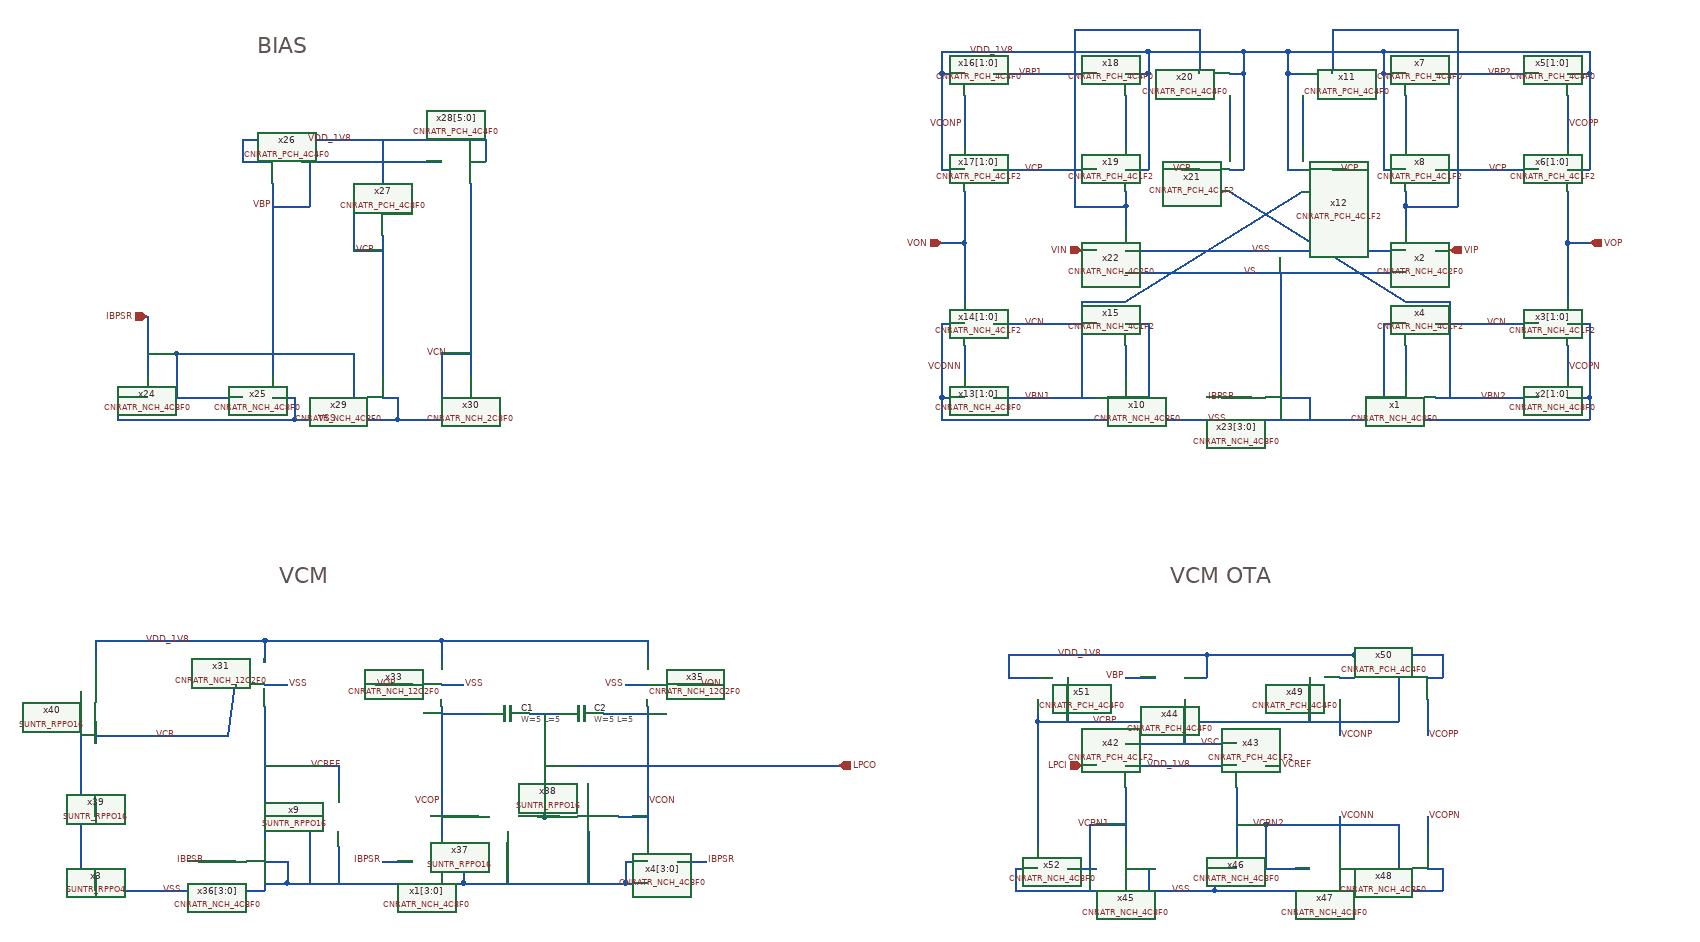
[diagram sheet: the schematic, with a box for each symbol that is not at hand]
v {xschem version=3.4.6 file_version=1.2}
G {}
K {}
V {}
S {}
E {}
T {BIAS} 530 -1300 0 0 1 1 {}
T {VCM} 560 -580 0 0 1 1 {}
T {VCM OTA} 1770 -580 0 0 1 1 {}
N 2060 -1250 2090 -1250 {
lab=VDD_1V8}
N 2060 -1280 2060 -1250 {
lab=VDD_1V8}
N 2060 -1280 2090 -1280 {
lab=VDD_1V8}
N 2310 -1250 2340 -1250 {
lab=VDD_1V8}
N 2340 -1280 2340 -1250 {
lab=VDD_1V8}
N 2310 -1280 2340 -1280 {
lab=VDD_1V8}
N 2310 -1220 2310 -1150 {
lab=VCOPP}
N 2090 -1220 2090 -1150 {
lab=#net1}
N 2060 -1120 2090 -1120 {
lab=VDD_1V8}
N 2060 -1250 2060 -1120 {
lab=VDD_1V8}
N 2310 -1120 2340 -1120 {
lab=VDD_1V8}
N 2340 -1250 2340 -1120 {
lab=VDD_1V8}
N 2090 -880 2090 -840 {
lab=#net2}
N 2060 -910 2090 -910 {
lab=VSS}
N 2060 -910 2060 -780 {
lab=VSS}
N 2060 -780 2090 -780 {
lab=VSS}
N 2060 -810 2090 -810 {
lab=VSS}
N 2310 -810 2340 -810 {
lab=VSS}
N 2340 -810 2340 -780 {
lab=VSS}
N 2310 -780 2340 -780 {
lab=VSS}
N 2310 -880 2310 -840 {
lab=VCOPN}
N 2310 -910 2340 -910 {
lab=VSS}
N 2340 -910 2340 -810 {
lab=VSS}
N 2090 -1280 2310 -1280 {
lab=VDD_1V8}
N 2130 -810 2270 -810 {
lab=VBN2}
N 2130 -1250 2270 -1250 {
lab=VBP2}
N 2090 -1090 2090 -1070 {
lab=VBP2}
N 2090 -940 2150 -940 {
lab=VBN2}
N 2150 -940 2150 -810 {
lab=VBN2}
N 2090 -780 2310 -780 {
lab=VSS}
N 1950 -1280 2060 -1280 {
lab=VDD_1V8}
N 1930 -1280 1950 -1280 {
lab=VDD_1V8}
N 1930 -1280 1930 -1250 {
lab=VDD_1V8}
N 1930 -1250 1950 -1250 {
lab=VDD_1V8}
N 1930 -1250 1930 -1120 {
lab=VDD_1V8}
N 1930 -1120 1950 -1120 {
lab=VDD_1V8}
N 1950 -1220 1950 -1150 {
lab=#net3}
N 2130 -1120 2270 -1120 {
lab=VCP}
N 2130 -910 2270 -910 {
lab=VCN}
N 1930 -780 1950 -780 {
lab=VSS}
N 2090 -1070 2090 -1040 {
lab=VBP2}
N 1950 -780 2060 -780 {
lab=VSS}
N 2160 -1250 2160 -1190 {
lab=VBP2}
N 2160 -1190 2160 -1070 {
lab=VBP2}
N 2090 -1070 2160 -1070 {
lab=VBP2}
N 1990 -1310 1990 -1250 {
lab=VBP2}
N 1990 -1310 2160 -1310 {
lab=VBP2}
N 2160 -1310 2160 -1250 {
lab=VBP2}
N 1990 -1120 2010 -1120 {
lab=VCP}
N 1930 -980 2090 -980 {
lab=VS}
N 1710 -1250 1740 -1250 {
lab=VDD_1V8}
N 1740 -1280 1740 -1250 {
lab=VDD_1V8}
N 1710 -1280 1740 -1280 {
lab=VDD_1V8}
N 1460 -1250 1490 -1250 {
lab=VDD_1V8}
N 1460 -1280 1460 -1250 {
lab=VDD_1V8}
N 1460 -1280 1490 -1280 {
lab=VDD_1V8}
N 1490 -1220 1490 -1150 {
lab=VCONP}
N 1710 -1220 1710 -1150 {
lab=#net4}
N 1710 -1120 1740 -1120 {
lab=VDD_1V8}
N 1740 -1250 1740 -1120 {
lab=VDD_1V8}
N 1460 -1120 1490 -1120 {
lab=VDD_1V8}
N 1460 -1250 1460 -1120 {
lab=VDD_1V8}
N 1710 -880 1710 -840 {
lab=#net5}
N 1710 -910 1740 -910 {
lab=VSS}
N 1740 -910 1740 -780 {
lab=VSS}
N 1710 -780 1740 -780 {
lab=VSS}
N 1710 -810 1740 -810 {
lab=VSS}
N 1460 -810 1490 -810 {
lab=VSS}
N 1460 -810 1460 -780 {
lab=VSS}
N 1460 -780 1490 -780 {
lab=VSS}
N 1490 -880 1490 -840 {
lab=VCONN}
N 1460 -910 1490 -910 {
lab=VSS}
N 1460 -910 1460 -810 {
lab=VSS}
N 1490 -1280 1710 -1280 {
lab=VDD_1V8}
N 1530 -810 1670 -810 {
lab=VBN1}
N 1530 -1250 1670 -1250 {
lab=VBP1}
N 1710 -1090 1710 -1070 {
lab=VBP1}
N 1650 -940 1710 -940 {
lab=VBN1}
N 1650 -940 1650 -810 {
lab=VBN1}
N 1490 -780 1710 -780 {
lab=VSS}
N 1740 -1280 1850 -1280 {
lab=VDD_1V8}
N 1850 -1280 1870 -1280 {
lab=VDD_1V8}
N 1870 -1280 1870 -1250 {
lab=VDD_1V8}
N 1850 -1250 1870 -1250 {
lab=VDD_1V8}
N 1870 -1250 1870 -1120 {
lab=VDD_1V8}
N 1850 -1120 1870 -1120 {
lab=VDD_1V8}
N 1850 -1220 1850 -1150 {
lab=#net6}
N 1530 -1120 1670 -1120 {
lab=VCP}
N 1530 -910 1670 -910 {
lab=VCN}
N 1850 -780 1870 -780 {
lab=VSS}
N 1710 -1070 1710 -1040 {
lab=VBP1}
N 1740 -780 1850 -780 {
lab=VSS}
N 1640 -1250 1640 -1190 {
lab=VBP1}
N 1640 -1190 1640 -1070 {
lab=VBP1}
N 1640 -1070 1710 -1070 {
lab=VBP1}
N 1810 -1310 1810 -1250 {
lab=VBP1}
N 1640 -1310 1810 -1310 {
lab=VBP1}
N 1640 -1310 1640 -1250 {
lab=VBP1}
N 1790 -1120 1810 -1120 {
lab=VCP}
N 1710 -980 1870 -980 {
lab=VS}
N 1870 -780 1930 -780 {
lab=VSS}
N 1870 -980 1930 -980 {
lab=VS}
N 1710 -1010 2090 -1010 {
lab=VSS}
N 1920 -810 1960 -810 {
lab=VSS}
N 1960 -810 1960 -780 {
lab=VSS}
N 1920 -980 1920 -840 {
lab=VS}
N 1870 -1280 1930 -1280 {
lab=VDD_1V8}
N 1840 -810 1880 -810 {
lab=IBPSR}
N 1650 -1010 1670 -1010 {
lab=VIN}
N 2130 -1010 2150 -1010 {
lab=VIP}
N 2310 -1020 2340 -1020 {
lab=VOP}
N 1460 -1020 1490 -1020 {
lab=VON}
N 380 -920 380 -840 {
lab=IBPSR}
N 340 -810 380 -810 {
lab=VSS}
N 340 -810 340 -780 {
lab=VSS}
N 340 -780 380 -780 {
lab=VSS}
N 420 -870 420 -810 {
lab=IBPSR}
N 380 -870 420 -870 {
lab=IBPSR}
N 420 -810 510 -810 {
lab=IBPSR}
N 550 -990 550 -840 {
lab=VBP}
N 550 -1100 550 -990 {
lab=VBP}
N 510 -1130 550 -1130 {
lab=VDD_1V8}
N 510 -1160 510 -1130 {
lab=VDD_1V8}
N 510 -1160 550 -1160 {
lab=VDD_1V8}
N 550 -1160 820 -1160 {
lab=VDD_1V8}
N 820 -1130 840 -1130 {
lab=VDD_1V8}
N 840 -1160 840 -1130 {
lab=VDD_1V8}
N 820 -1160 840 -1160 {
lab=VDD_1V8}
N 590 -1130 780 -1130 {
lab=VBP}
N 550 -1070 600 -1070 {
lab=VBP}
N 600 -1130 600 -1070 {
lab=VBP}
N 700 -1030 700 -840 {
lab=VCP}
N 420 -870 660 -870 {
lab=IBPSR}
N 660 -870 660 -810 {
lab=IBPSR}
N 550 -810 580 -810 {
lab=VSS}
N 580 -810 580 -780 {
lab=VSS}
N 550 -780 580 -780 {
lab=VSS}
N 380 -780 550 -780 {
lab=VSS}
N 580 -780 700 -780 {
lab=VSS}
N 700 -810 720 -810 {
lab=VSS}
N 720 -810 720 -780 {
lab=VSS}
N 700 -780 720 -780 {
lab=VSS}
N 700 -1060 730 -1060 {
lab=VDD_1V8}
N 730 -1090 730 -1060 {
lab=VDD_1V8}
N 700 -1090 730 -1090 {
lab=VDD_1V8}
N 700 -1160 700 -1090 {
lab=VDD_1V8}
N 820 -1100 820 -840 {
lab=VCN}
N 820 -810 840 -810 {
lab=VSS}
N 840 -810 840 -780 {
lab=VSS}
N 820 -780 840 -780 {
lab=VSS}
N 720 -780 820 -780 {
lab=VSS}
N 780 -870 780 -810 {
lab=VCN}
N 780 -870 820 -870 {
lab=VCN}
N 660 -1060 660 -1010 {
lab=VCP}
N 660 -1010 700 -1010 {
lab=VCP}
N 540 -390 540 -210 {
lab=VCREF}
N 540 -180 570 -180 {
lab=VSS}
N 570 -180 570 -150 {
lab=VSS}
N 540 -150 570 -150 {
lab=VSS}
N 540 -420 570 -420 {
lab=VSS}
N 540 -480 540 -450 {
lab=VDD_1V8}
N 540 -480 570 -480 {
lab=VDD_1V8}
N 780 -390 780 -210 {
lab=VCOP}
N 780 -180 810 -180 {
lab=VSS}
N 810 -180 810 -150 {
lab=VSS}
N 780 -150 810 -150 {
lab=VSS}
N 780 -420 810 -420 {
lab=VSS}
N 780 -480 780 -450 {
lab=VDD_1V8}
N 780 -480 810 -480 {
lab=VDD_1V8}
N 1060 -390 1060 -210 {
lab=VCON}
N 1030 -180 1060 -180 {
lab=VSS}
N 1030 -180 1030 -150 {
lab=VSS}
N 1030 -150 1060 -150 {
lab=VSS}
N 1030 -420 1060 -420 {
lab=VSS}
N 1060 -480 1060 -450 {
lab=VDD_1V8}
N 1030 -480 1060 -480 {
lab=VDD_1V8}
N 920 -240 940 -240 {
lab=LPCO}
N 910 -240 920 -240 {
lab=LPCO}
N 900 -380 940 -380 {
lab=LPCO}
N 920 -380 920 -240 {
lab=LPCO}
N 780 -380 840 -380 {
lab=VCOP}
N 780 -240 830 -240 {
lab=VCOP}
N 1020 -240 1060 -240 {
lab=VCON}
N 1000 -380 1060 -380 {
lab=VCON}
N 810 -480 1030 -480 {
lab=VDD_1V8}
N 570 -480 780 -480 {
lab=VDD_1V8}
N 700 -180 740 -180 {
lab=IBPSR}
N 450 -180 500 -180 {
lab=IBPSR}
N 1100 -180 1140 -180 {
lab=IBPSR}
N 810 -150 1030 -150 {
lab=VSS}
N 570 -150 780 -150 {
lab=VSS}
N 870 -220 870 -150 {
lab=VSS}
N 980 -220 980 -150 {
lab=VSS}
N 290 -410 290 -300 {
lab=VSS}
N 290 -300 290 -140 {
lab=VSS}
N 290 -140 540 -140 {
lab=VSS}
N 540 -150 540 -140 {
lab=VSS}
N 310 -370 310 -340 {
lab=VCR}
N 310 -480 310 -450 {
lab=VDD_1V8}
N 310 -480 540 -480 {
lab=VDD_1V8}
N 310 -350 490 -350 {
lab=VCR}
N 490 -350 500 -420 {
lab=VCR}
N 540 -310 610 -310 {
lab=VCREF}
N 690 -420 740 -420 {
lab=VOP}
N 1100 -420 1150 -420 {
lab=VON}
N 2000 -430 2020 -430 {
lab=VDD_1V8}
N 2020 -460 2020 -430 {
lab=VDD_1V8}
N 2000 -460 2020 -460 {
lab=VDD_1V8}
N 2120 -430 2140 -430 {
lab=VDD_1V8}
N 2140 -460 2140 -430 {
lab=VDD_1V8}
N 2120 -460 2140 -460 {
lab=VDD_1V8}
N 2020 -460 2120 -460 {
lab=VDD_1V8}
N 2120 -170 2140 -170 {
lab=VSS}
N 2140 -170 2140 -140 {
lab=VSS}
N 2120 -140 2140 -140 {
lab=VSS}
N 2000 -140 2120 -140 {
lab=VSS}
N 2000 -170 2020 -170 {
lab=VSS}
N 2020 -170 2020 -140 {
lab=VSS}
N 1830 -170 1860 -170 {
lab=VSS}
N 1830 -170 1830 -140 {
lab=VSS}
N 1830 -140 1860 -140 {
lab=VSS}
N 1860 -140 2000 -140 {
lab=VSS}
N 1710 -140 1830 -140 {
lab=VSS}
N 1710 -170 1740 -170 {
lab=VSS}
N 1740 -170 1740 -140 {
lab=VSS}
N 1710 -280 1710 -200 {
lab=VCBN1}
N 1860 -280 1860 -200 {
lab=VCBN2}
N 1860 -230 1900 -230 {
lab=VCBN2}
N 1900 -230 1900 -170 {
lab=VCBN2}
N 1900 -170 1960 -170 {
lab=VCBN2}
N 1900 -230 2080 -230 {
lab=VCBN2}
N 2080 -230 2080 -170 {
lab=VCBN2}
N 1590 -400 1590 -370 {
lab=VCBP}
N 1590 -370 2080 -370 {
lab=VCBP}
N 2080 -430 2080 -370 {
lab=VCBP}
N 1960 -430 1960 -370 {
lab=VCBP}
N 1590 -370 1590 -200 {
lab=VCBP}
N 1630 -170 1670 -170 {
lab=VCBN1}
N 1660 -230 1710 -230 {
lab=VCBN1}
N 1660 -230 1660 -170 {
lab=VCBN1}
N 1590 -140 1710 -140 {
lab=VSS}
N 1560 -170 1590 -170 {
lab=VSS}
N 1560 -170 1560 -140 {
lab=VSS}
N 1560 -140 1590 -140 {
lab=VSS}
N 1550 -430 1590 -430 {
lab=VDD_1V8}
N 1550 -460 1550 -430 {
lab=VDD_1V8}
N 1550 -460 1590 -460 {
lab=VDD_1V8}
N 1630 -430 1630 -370 {
lab=VCBP}
N 1710 -340 1860 -340 {
lab=VSC}
N 1710 -310 1860 -310 {
lab=VDD_1V8}
N 1790 -400 1790 -340 {
lab=VSC}
N 1790 -430 1820 -430 {
lab=VDD_1V8}
N 1820 -460 1820 -430 {
lab=VDD_1V8}
N 1790 -460 1820 -460 {
lab=VDD_1V8}
N 1820 -460 2000 -460 {
lab=VDD_1V8}
N 1590 -460 1790 -460 {
lab=VDD_1V8}
N 1900 -310 1920 -310 {
lab=VCREF}
N 1650 -310 1670 -310 {
lab=LPCI}
N 2000 -400 2000 -350 {
lab=VCONP}
N 2120 -400 2120 -350 {
lab=VCOPP}
N 2000 -240 2000 -200 {
lab=VCONN}
N 2120 -240 2120 -200 {
lab=VCOPN}
N 1710 -430 1750 -430 {
lab=VBP}
N 1710 -940 1950 -1090 {
lab=VBN1}
N 1850 -1090 2090 -940 {
lab=VBN2}
N 640 -310 640 -280 {
lab=VCREF}
N 610 -310 640 -310 {
lab=VCREF}
N 600 -240 620 -240 {
lab=VSS}
N 600 -240 600 -150 {
lab=VSS}
N 640 -200 640 -150 {
lab=VSS}
N 1490 -1020 1490 -940 {
lab=VON}
N 2310 -1020 2310 -940 {
lab=VOP}
N 1490 -1090 1490 -1020 {
lab=VON}
N 2310 -1090 2310 -1020 {
lab=VOP}
N 920 -310 1320 -310 {
lab=LPCO}
N 310 -260 310 -240 {
lab=#net7}
N 310 -160 310 -140 {
lab=VSS}
C {devices/ipin.sym} 1650 -1010 0 0 {name=p3 lab=VIN}
C {CNR_ATR_SKY130NM/CNRATR_NCH_4C8F0.sym} 2130 -810 0 1 {name=x1 }
C {CNR_ATR_SKY130NM/CNRATR_NCH_4C8F0.sym} 2270 -810 0 0 {name=x2[1:0]}
C {CNR_ATR_SKY130NM/CNRATR_NCH_4C1F2.sym} 2270 -910 0 0 {name=x3[1:0]}
C {CNR_ATR_SKY130NM/CNRATR_NCH_4C1F2.sym} 2130 -910 0 1 {name=x4 }
C {CNR_ATR_SKY130NM/CNRATR_PCH_4C4F0.sym} 2270 -1250 0 0 {name=x5[1:0]}
C {CNR_ATR_SKY130NM/CNRATR_PCH_4C1F2.sym} 2270 -1120 0 0 {name=x6[1:0]}
C {CNR_ATR_SKY130NM/CNRATR_PCH_4C4F0.sym} 2130 -1250 0 1 {name=x7 }
C {CNR_ATR_SKY130NM/CNRATR_PCH_4C1F2.sym} 2130 -1120 0 1 {name=x8 }
C {CNR_ATR_SKY130NM/CNRATR_PCH_4C4F0.sym} 1990 -1250 0 1 {name=x11 }
C {CNR_ATR_SKY130NM/CNRATR_PCH_4C1F2.sym} 1990 -1120 0 1 {name=x12 }
C {CNR_ATR_SKY130NM/CNRATR_NCH_4C2F0.sym} 2130 -1010 0 1 {name=x2}
C {devices/lab_wire.sym} 2230 -1120 0 0 {name=p6 sig_type=std_logic lab=VCP}
C {devices/lab_wire.sym} 2000 -1120 0 1 {name=p5 sig_type=std_logic lab=VCP}
C {devices/lab_wire.sym} 2200 -1250 0 1 {name=p7 sig_type=std_logic lab=VBP2}
C {devices/lab_wire.sym} 2310 -1180 0 1 {name=p8 sig_type=std_logic lab=VCOPP}
C {devices/lab_wire.sym} 2310 -850 0 1 {name=p9 sig_type=std_logic lab=VCOPN}
C {devices/lab_wire.sym} 2230 -910 0 0 {name=p4 sig_type=std_logic lab=VCN}
C {devices/lab_wire.sym} 2230 -810 0 0 {name=p10 sig_type=std_logic lab=VBN2
}
C {CNR_ATR_SKY130NM/CNRATR_NCH_4C8F0.sym} 1670 -810 0 0 {name=x10 }
C {CNR_ATR_SKY130NM/CNRATR_NCH_4C8F0.sym} 1530 -810 0 1 {name=x13[1:0]}
C {CNR_ATR_SKY130NM/CNRATR_NCH_4C1F2.sym} 1530 -910 0 1 {name=x14[1:0]}
C {CNR_ATR_SKY130NM/CNRATR_NCH_4C1F2.sym} 1670 -910 0 0 {name=x15 }
C {CNR_ATR_SKY130NM/CNRATR_PCH_4C4F0.sym} 1530 -1250 0 1 {name=x16[1:0]}
C {CNR_ATR_SKY130NM/CNRATR_PCH_4C1F2.sym} 1530 -1120 0 1 {name=x17[1:0]}
C {CNR_ATR_SKY130NM/CNRATR_PCH_4C4F0.sym} 1670 -1250 0 0 {name=x18 }
C {CNR_ATR_SKY130NM/CNRATR_PCH_4C1F2.sym} 1670 -1120 0 0 {name=x19 }
C {CNR_ATR_SKY130NM/CNRATR_PCH_4C4F0.sym} 1810 -1250 0 0 {name=x20 }
C {CNR_ATR_SKY130NM/CNRATR_PCH_4C1F2.sym} 1810 -1120 0 0 {name=x21 }
C {CNR_ATR_SKY130NM/CNRATR_NCH_4C2F0.sym} 1670 -1010 0 0 {name=x22}
C {devices/lab_wire.sym} 1570 -1120 0 1 {name=p11 sig_type=std_logic lab=VCP}
C {devices/lab_wire.sym} 1800 -1120 0 0 {name=p12 sig_type=std_logic lab=VCP}
C {devices/lab_wire.sym} 1600 -1250 0 0 {name=p13 sig_type=std_logic lab=VBP1}
C {devices/lab_wire.sym} 1490 -1180 0 0 {name=p14 sig_type=std_logic lab=VCONP}
C {devices/lab_wire.sym} 1490 -850 0 0 {name=p15 sig_type=std_logic lab=VCONN}
C {devices/lab_wire.sym} 1570 -910 0 1 {name=p16 sig_type=std_logic lab=VCN}
C {devices/lab_wire.sym} 1570 -810 0 1 {name=p17 sig_type=std_logic lab=VBN1
}
C {CNR_ATR_SKY130NM/CNRATR_NCH_4C8F0.sym} 1880 -810 0 0 {name=x23[3:0]}
C {devices/lab_wire.sym} 1560 -1280 0 0 {name=p18 sig_type=std_logic lab=VDD_1V8}
C {devices/lab_wire.sym} 1850 -780 0 0 {name=p19 sig_type=std_logic lab=VSS}
C {devices/lab_wire.sym} 1860 -810 0 0 {name=p20 sig_type=std_logic lab=IBPSR
}
C {devices/ipin.sym} 2150 -1010 0 1 {name=p21 lab=VIP}
C {devices/opin.sym} 2340 -1020 0 0 {name=p22 lab=VOP}
C {devices/opin.sym} 1460 -1020 0 1 {name=p23 lab=VON}
C {CNR_ATR_SKY130NM/CNRATR_NCH_4C8F0.sym} 420 -810 0 1 {name=x24 }
C {devices/ipin.sym} 380 -920 0 0 {name=p24 lab=IBPSR
}
C {CNR_ATR_SKY130NM/CNRATR_NCH_4C8F0.sym} 510 -810 0 0 {name=x25 }
C {CNR_ATR_SKY130NM/CNRATR_PCH_4C4F0.sym} 590 -1130 0 1 {name=x26 }
C {CNR_ATR_SKY130NM/CNRATR_PCH_4C8F0.sym} 660 -1060 0 0 {name=x27 }
C {CNR_ATR_SKY130NM/CNRATR_PCH_4C4F0.sym} 780 -1130 0 0 {name=x28[5:0]}
C {CNR_ATR_SKY130NM/CNRATR_NCH_4C8F0.sym} 660 -810 0 0 {name=x29}
C {CNR_ATR_SKY130NM/CNRATR_NCH_2C8F0.sym} 780 -810 0 0 {name=x30 }
C {devices/lab_wire.sym} 790 -870 0 0 {name=p25 sig_type=std_logic lab=VCN}
C {devices/lab_wire.sym} 690 -1010 0 0 {name=p26 sig_type=std_logic lab=VCP}
C {CNR_ATR_SKY130NM/CNRATR_NCH_12C2F0.sym} 500 -420 0 0 {name=x31 }
C {CNR_ATR_SKY130NM/CNRATR_NCH_4C8F0.sym} 500 -180 0 0 {name=x36[3:0]}
C {CNR_ATR_SKY130NM/CNRATR_NCH_12C2F0.sym} 740 -420 0 0 {name=x33 }
C {CNR_ATR_SKY130NM/CNRATR_NCH_4C8F0.sym} 740 -180 0 0 {name=x1[3:0]}
C {CNR_ATR_SKY130NM/CNRATR_NCH_12C2F0.sym} 1100 -420 0 1 {name=x35 }
C {CNR_ATR_SKY130NM/CNRATR_NCH_4C8F0.sym} 1100 -180 0 1 {name=x4[3:0]}
C {sky130_fd_pr/cap_mim_m3_1.sym} 870 -380 1 0 {name=C1 model=cap_mim_m3_1 W=5 L=5 MF=1 spiceprefix=X}
C {sky130_fd_pr/cap_mim_m3_1.sym} 970 -380 1 0 {name=C2 model=cap_mim_m3_1 W=5 L=5 MF=1 spiceprefix=X}
C {SUN_TR_SKY130NM/SUNTR_RPPO16.sym} 830 -240 0 0 {name=x37 }
C {SUN_TR_SKY130NM/SUNTR_RPPO16.sym} 940 -240 0 0 {name=x38 }
C {devices/lab_wire.sym} 460 -180 0 0 {name=p27 sig_type=std_logic lab=IBPSR
}
C {devices/lab_wire.sym} 700 -180 0 0 {name=p28 sig_type=std_logic lab=IBPSR
}
C {devices/lab_wire.sym} 1140 -180 0 1 {name=p29 sig_type=std_logic lab=IBPSR
}
C {SUN_TR_SKY130NM/SUNTR_RPPO16.sym} 310 -260 1 1 {name=x39 }
C {SUN_TR_SKY130NM/SUNTR_RPPO16.sym} 310 -370 1 1 {name=x40 }
C {devices/lab_wire.sym} 600 -310 0 1 {name=p30 sig_type=std_logic lab=VCREF
}
C {devices/lab_wire.sym} 660 -1160 0 0 {name=p32 sig_type=std_logic lab=VDD_1V8}
C {devices/lab_wire.sym} 440 -480 0 0 {name=p33 sig_type=std_logic lab=VDD_1V8}
C {devices/lab_wire.sym} 430 -140 0 0 {name=p34 sig_type=std_logic lab=VSS}
C {devices/lab_wire.sym} 640 -780 0 0 {name=p35 sig_type=std_logic lab=VSS}
C {devices/lab_wire.sym} 720 -420 0 0 {name=p36 sig_type=std_logic lab=VOP
}
C {devices/lab_wire.sym} 1130 -420 0 1 {name=p37 sig_type=std_logic lab=VON
}
C {CNR_ATR_SKY130NM/CNRATR_PCH_4C1F2.sym} 1670 -310 0 0 {name=x42 }
C {CNR_ATR_SKY130NM/CNRATR_PCH_4C1F2.sym} 1900 -310 0 1 {name=x43 }
C {devices/lab_wire.sym} 550 -1070 0 0 {name=p38 sig_type=std_logic lab=VBP}
C {CNR_ATR_SKY130NM/CNRATR_PCH_4C4F0.sym} 1750 -430 0 0 {name=x44 }
C {CNR_ATR_SKY130NM/CNRATR_NCH_4C8F0.sym} 1670 -170 0 0 {name=x45 }
C {CNR_ATR_SKY130NM/CNRATR_NCH_4C8F0.sym} 1900 -170 0 1 {name=x46 }
C {CNR_ATR_SKY130NM/CNRATR_NCH_4C8F0.sym} 1960 -170 0 0 {name=x47 }
C {CNR_ATR_SKY130NM/CNRATR_NCH_4C8F0.sym} 2080 -170 0 0 {name=x48 }
C {CNR_ATR_SKY130NM/CNRATR_PCH_4C4F0.sym} 1960 -430 0 0 {name=x49 }
C {CNR_ATR_SKY130NM/CNRATR_PCH_4C4F0.sym} 2080 -430 0 0 {name=x50 }
C {CNR_ATR_SKY130NM/CNRATR_PCH_4C4F0.sym} 1630 -430 0 1 {name=x51 }
C {CNR_ATR_SKY130NM/CNRATR_NCH_4C8F0.sym} 1630 -170 0 1 {name=x52 }
C {devices/lab_wire.sym} 1680 -460 0 0 {name=p39 sig_type=std_logic lab=VDD_1V8}
C {devices/lab_wire.sym} 1800 -140 0 0 {name=p40 sig_type=std_logic lab=VSS}
C {devices/lab_wire.sym} 1920 -310 0 1 {name=p42 sig_type=std_logic lab=VCREF
}
C {devices/lab_wire.sym} 1800 -310 0 0 {name=p43 sig_type=std_logic lab=VDD_1V8
}
C {devices/lab_wire.sym} 1910 -1010 0 0 {name=p48 sig_type=std_logic lab=VSS}
C {devices/lab_wire.sym} 1890 -980 0 0 {name=p49 sig_type=std_logic lab=VS}
C {devices/lab_wire.sym} 1700 -370 0 0 {name=p50 sig_type=std_logic lab=VCBP
}
C {devices/lab_wire.sym} 1810 -340 0 1 {name=p51 sig_type=std_logic lab=VSC
}
C {devices/lab_wire.sym} 1710 -430 0 0 {name=p52 sig_type=std_logic lab=VBP
}
C {SUN_TR_SKY130NM/SUNTR_RPPO16.sym} 640 -280 1 0 {name=x9 }
C {devices/ipin.sym} 1650 -310 0 0 {name=p53 lab=LPCI}
C {devices/opin.sym} 1320 -310 0 0 {name=p54 lab=LPCO}
C {devices/lab_wire.sym} 1880 -230 0 1 {name=p31 sig_type=std_logic lab=VCBN2
}
C {devices/lab_wire.sym} 1690 -230 0 0 {name=p41 sig_type=std_logic lab=VCBN1
}
C {devices/lab_wire.sym} 1060 -260 0 1 {name=p55 sig_type=std_logic lab=VCON
}
C {devices/lab_wire.sym} 780 -260 0 0 {name=p56 sig_type=std_logic lab=VCOP
}
C {devices/lab_wire.sym} 420 -350 0 0 {name=p57 sig_type=std_logic lab=VCR
}
C {devices/lab_wire.sym} 2120 -350 0 1 {name=p44 sig_type=std_logic lab=VCOPP}
C {devices/lab_wire.sym} 2000 -350 0 1 {name=p45 sig_type=std_logic lab=VCONP}
C {devices/lab_wire.sym} 2000 -240 0 1 {name=p46 sig_type=std_logic lab=VCONN}
C {devices/lab_wire.sym} 2120 -240 0 1 {name=p47 sig_type=std_logic lab=VCOPN}
C {devices/lab_wire.sym} 570 -420 0 1 {name=p58 sig_type=std_logic lab=VSS}
C {devices/lab_wire.sym} 810 -420 0 1 {name=p59 sig_type=std_logic lab=VSS}
C {devices/lab_wire.sym} 1030 -420 0 0 {name=p60 sig_type=std_logic lab=VSS}
C {SUN_TR_SKY130NM/SUNTR_RPPO4.sym} 310 -160 1 1 {name=x3 }
